VERSION 5.7 ;
  NOWIREEXTENSIONATPIN ON ;
  DIVIDERCHAR "/" ;
  BUSBITCHARS "[]" ;
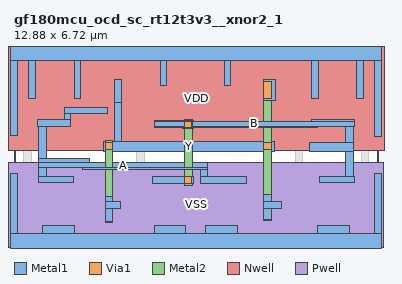
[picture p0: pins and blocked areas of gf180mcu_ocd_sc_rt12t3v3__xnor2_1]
MACRO gf180mcu_ocd_sc_rt12t3v3__xnor2_1
  CLASS CORE ;
  FOREIGN gf180mcu_ocd_sc_rt12t3v3__xnor2_1 ;
  ORIGIN 0.000 0.000 ;
  SIZE 12.880 BY 6.720 ;
  SYMMETRY X Y ;
  SITE unithd ;
  PIN A
    DIRECTION INPUT ;
    USE SIGNAL ;
    ANTENNAGATEAREA 3.344600 ;
    PORT
      LAYER Metal1 ;
        RECT 1.785 4.540 3.315 4.770 ;
        RECT 1.785 4.320 2.015 4.540 ;
        RECT 0.845 4.090 2.015 4.320 ;
        RECT 0.880 2.965 1.140 4.090 ;
        RECT 0.880 2.810 2.660 2.965 ;
        RECT 0.880 2.635 6.845 2.810 ;
        RECT 0.880 2.325 1.140 2.635 ;
        RECT 2.430 2.555 6.845 2.635 ;
        RECT 0.850 2.095 2.105 2.325 ;
        RECT 6.590 2.320 6.845 2.555 ;
        RECT 6.590 2.075 8.235 2.320 ;
        RECT 8.005 2.070 8.235 2.075 ;
    END
  END A
  PIN B
    DIRECTION INPUT ;
    USE SIGNAL ;
    ANTENNAGATEAREA 3.344600 ;
    PORT
      LAYER Metal1 ;
        RECT 4.970 4.280 6.070 4.290 ;
        RECT 4.970 4.265 6.350 4.280 ;
        RECT 10.525 4.265 12.035 4.320 ;
        RECT 4.970 4.090 12.035 4.265 ;
        RECT 4.970 4.060 10.745 4.090 ;
        RECT 5.970 4.035 10.745 4.060 ;
        RECT 5.970 4.020 6.350 4.035 ;
        RECT 11.740 3.525 12.000 4.090 ;
        RECT 10.450 3.195 12.000 3.525 ;
        RECT 11.740 2.325 12.000 3.195 ;
        RECT 5.970 2.320 6.350 2.325 ;
        RECT 4.905 2.075 6.350 2.320 ;
        RECT 10.790 2.095 12.030 2.325 ;
        RECT 5.970 2.065 6.350 2.075 ;
      LAYER Via1 ;
        RECT 6.030 4.020 6.290 4.280 ;
        RECT 6.030 2.065 6.290 2.325 ;
      LAYER Metal2 ;
        RECT 6.020 2.005 6.300 4.340 ;
    END
  END B
  PIN Y
    DIRECTION OUTPUT ;
    USE SIGNAL ;
    ANTENNADIFFAREA 1.953800 ;
    PORT
      LAYER Metal1 ;
        RECT 3.550 4.945 3.810 5.730 ;
        RECT 8.830 5.000 9.260 5.730 ;
        RECT 3.555 3.540 3.810 4.945 ;
        RECT 3.150 3.205 9.210 3.540 ;
        RECT 3.590 3.200 6.030 3.205 ;
        RECT 3.230 1.425 3.490 1.600 ;
        RECT 8.830 1.425 9.090 1.670 ;
        RECT 3.230 1.195 3.760 1.425 ;
        RECT 8.830 1.195 9.465 1.425 ;
        RECT 3.230 0.730 3.490 1.195 ;
        RECT 8.830 0.800 9.090 1.195 ;
      LAYER Via1 ;
        RECT 8.830 5.060 9.090 5.665 ;
        RECT 3.230 3.255 3.490 3.515 ;
        RECT 8.830 3.255 9.090 3.515 ;
        RECT 3.230 0.790 3.490 1.540 ;
        RECT 8.830 0.860 9.090 1.605 ;
      LAYER Metal2 ;
        RECT 3.220 0.690 3.500 3.575 ;
        RECT 8.820 0.770 9.100 5.735 ;
    END
  END Y
  PIN VDD
    DIRECTION INOUT ;
    USE POWER ;
    SHAPE ABUTMENT ;
    PORT
      LAYER Nwell ;
        RECT -0.660 3.245 13.440 7.330 ;
      LAYER Metal1 ;
        RECT -0.115 6.420 12.995 7.020 ;
        RECT -0.115 3.750 0.115 6.420 ;
        RECT 0.525 5.060 0.755 6.420 ;
        RECT 2.125 5.065 2.355 6.420 ;
        RECT 5.165 5.520 5.395 6.420 ;
        RECT 7.430 5.520 7.660 6.420 ;
        RECT 10.525 5.065 10.755 6.420 ;
        RECT 12.125 5.060 12.355 6.420 ;
        RECT 12.765 3.745 12.995 6.420 ;
    END
  END VDD
  PIN VSS
    DIRECTION INOUT ;
    USE GROUND ;
    SHAPE ABUTMENT ;
    PORT
      LAYER Pwell ;
        RECT -0.180 -0.180 13.060 2.815 ;
      LAYER Metal1 ;
        RECT -0.115 0.300 0.115 2.410 ;
        RECT 1.020 0.300 2.130 0.585 ;
        RECT 4.970 0.300 6.080 0.585 ;
        RECT 6.790 0.300 7.900 0.585 ;
        RECT 10.750 0.300 11.860 0.585 ;
        RECT 12.765 0.300 12.995 2.410 ;
        RECT -0.115 -0.300 12.995 0.300 ;
    END
  END VSS
  OBS
      LAYER Metal1 ;
        RECT 1.325 4.820 1.555 6.180 ;
        RECT 2.765 5.960 4.595 6.190 ;
        RECT 2.765 5.055 2.995 5.960 ;
        RECT 4.365 5.290 4.595 5.960 ;
        RECT 5.965 5.290 6.195 6.190 ;
        RECT 4.365 5.060 6.195 5.290 ;
        RECT 6.630 5.290 6.860 6.190 ;
        RECT 8.230 5.960 10.060 6.190 ;
        RECT 8.230 5.290 8.460 5.960 ;
        RECT 6.630 5.060 8.460 5.290 ;
        RECT 9.830 5.055 10.060 5.960 ;
        RECT 0.345 4.560 1.555 4.820 ;
        RECT 11.325 4.820 11.555 6.180 ;
        RECT 4.290 4.770 4.675 4.775 ;
        RECT 0.345 1.425 0.605 4.560 ;
        RECT 4.290 4.540 7.950 4.770 ;
        RECT 9.135 4.540 10.270 4.770 ;
        RECT 11.325 4.560 12.535 4.820 ;
        RECT 4.290 4.515 4.675 4.540 ;
        RECT 9.890 4.510 10.270 4.540 ;
        RECT 9.890 2.330 10.270 2.340 ;
        RECT 9.890 2.325 10.465 2.330 ;
        RECT 2.510 2.095 4.670 2.325 ;
        RECT 8.710 2.095 10.465 2.325 ;
        RECT 2.510 1.425 2.740 2.095 ;
        RECT 4.290 2.065 4.670 2.095 ;
        RECT 9.890 2.080 10.465 2.095 ;
        RECT 0.345 1.195 2.740 1.425 ;
        RECT 4.300 1.425 4.530 1.815 ;
        RECT 8.340 1.425 8.570 1.815 ;
        RECT 4.300 1.195 5.700 1.425 ;
        RECT 7.170 1.195 8.570 1.425 ;
        RECT 10.220 1.425 10.465 2.080 ;
        RECT 12.275 1.425 12.535 4.560 ;
        RECT 10.220 1.195 12.535 1.425 ;
        RECT 4.300 0.770 4.530 1.195 ;
        RECT 8.340 0.770 8.570 1.195 ;
      LAYER Via1 ;
        RECT 4.350 4.515 4.610 4.775 ;
        RECT 9.950 4.510 10.210 4.770 ;
        RECT 4.350 2.065 4.610 2.325 ;
        RECT 9.950 2.080 10.210 2.340 ;
      LAYER Metal2 ;
        RECT 4.340 1.990 4.620 4.870 ;
        RECT 9.940 2.000 10.220 4.840 ;
  END
END gf180mcu_ocd_sc_rt12t3v3__xnor2_1
END LIBRARY

